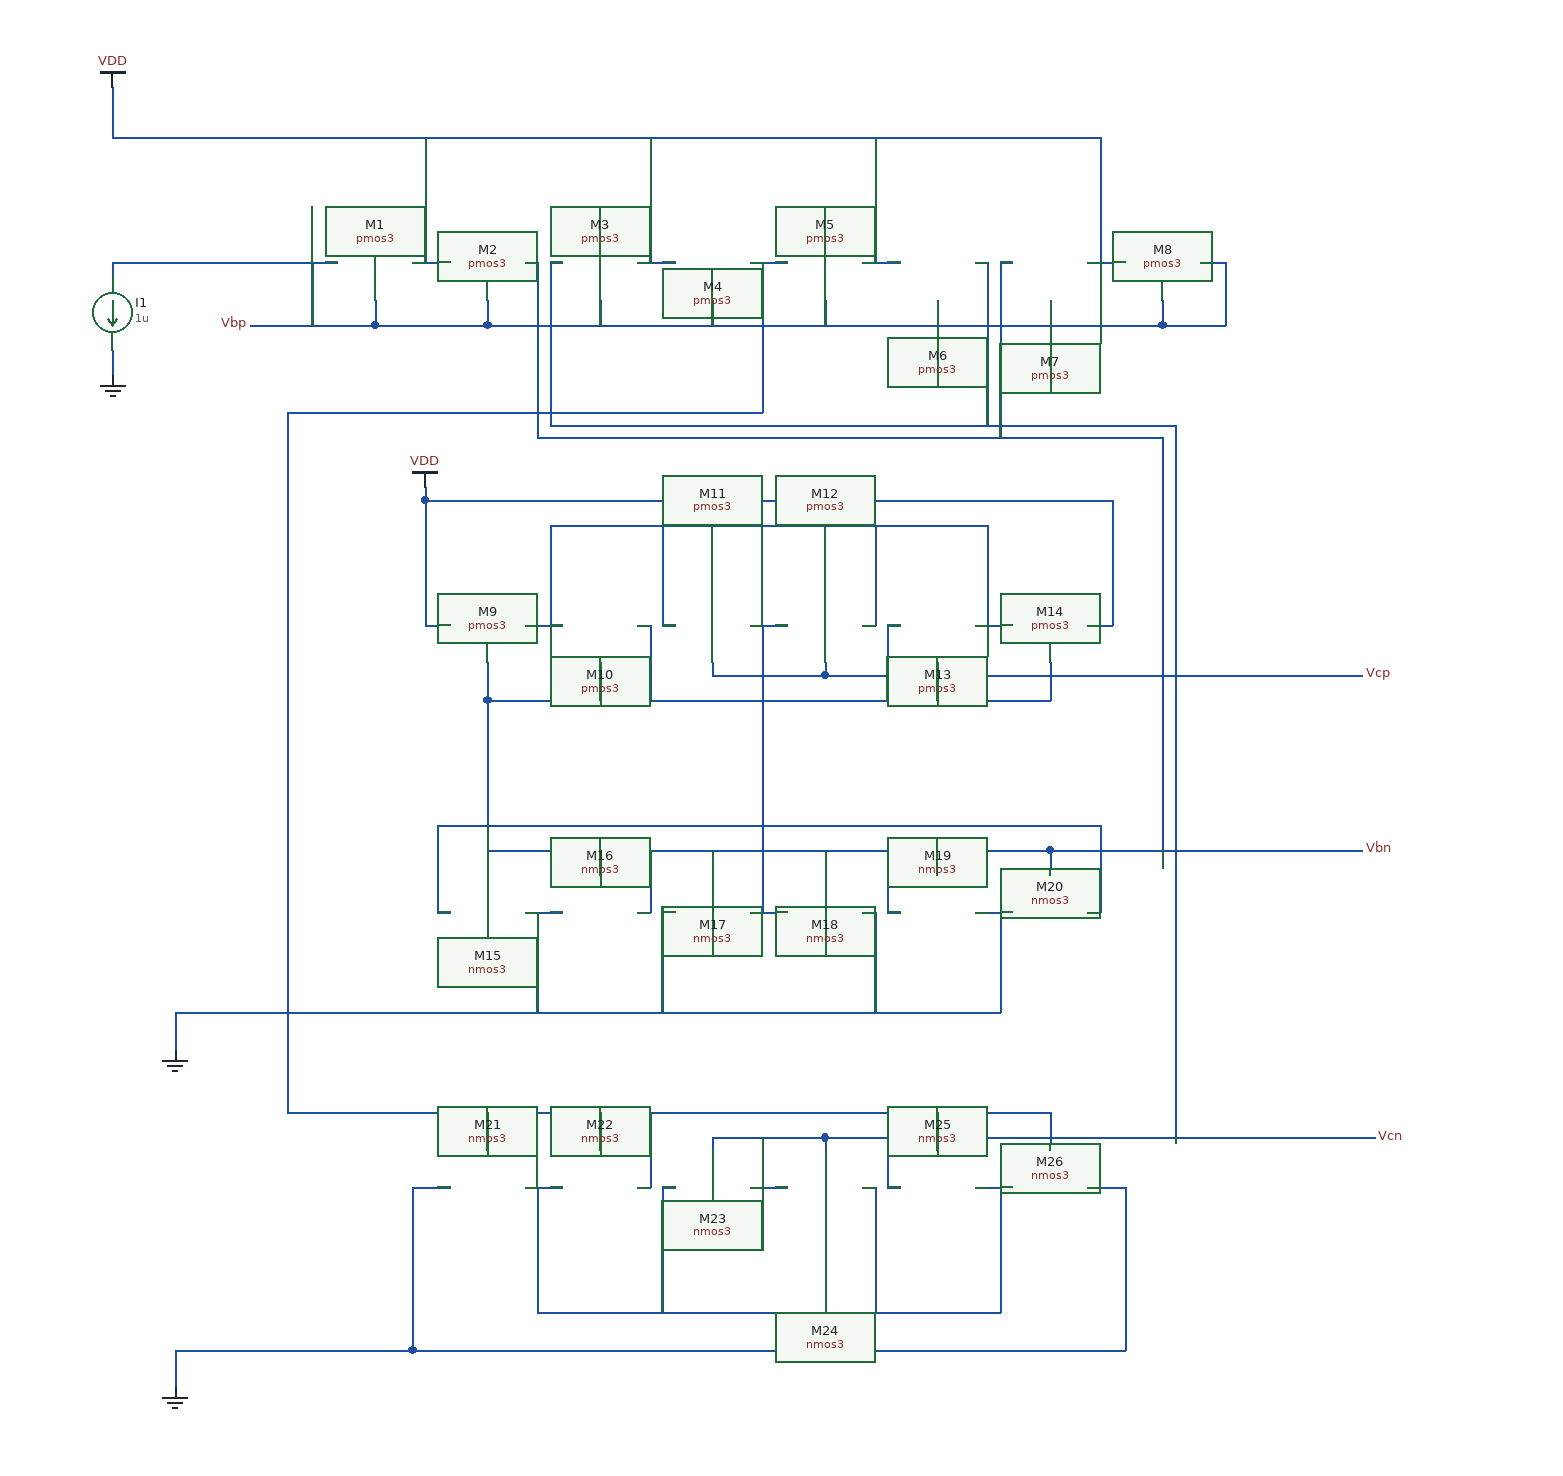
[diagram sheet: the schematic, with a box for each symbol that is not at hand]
v {xschem version=2.9.9 file_version=1.2 }
G {}
K {}
V {}
S {}
E {}
N 430 -980 430 -960 { lab=Vbp}
N 430 -960 520 -960 { lab=Vbp}
N 520 -980 520 -960 { lab=Vbp}
N 520 -960 1060 -960 { lab=Vbp}
N 1060 -980 1060 -960 { lab=Vbp}
N 970 -980 970 -960 { lab=Vbp}
N 880 -980 880 -960 { lab=Vbp}
N 790 -980 790 -960 { lab=Vbp}
N 700 -980 700 -960 { lab=Vbp}
N 610 -980 610 -960 { lab=Vbp}
N 330 -960 430 -960 { lab=Vbp}
N 220 -1010 400 -1010 { lab=Vbp}
N 220 -1010 220 -1000 { lab=Vbp}
N 220 -940 220 -920 { lab=GND}
N 460 -1010 490 -1010 { lab=VDD}
N 640 -1010 670 -1010 { lab=VDD}
N 820 -1010 850 -1010 { lab=VDD}
N 830 -1110 830 -1010 { lab=VDD}
N 220 -1110 920 -1110 { lab=VDD}
N 220 -1150 220 -1110 { lab=VDD}
N 470 -1110 470 -1010 { lab=VDD}
N 650 -1110 650 -1010 { lab=VDD}
N 380 -1010 380 -960 { lab=Vbp}
N 1090 -1010 1110 -1010 { lab=Vbp}
N 1110 -1010 1110 -960 { lab=Vbp}
N 1060 -960 1110 -960 { lab=Vbp}
N 470 -720 490 -720 { lab=VDD}
N 470 -800 470 -720 { lab=VDD}
N 1000 -720 1020 -720 { lab=VDD}
N 1020 -800 1020 -720 { lab=VDD}
N 470 -820 1020 -820 { lab=VDD}
N 520 -690 520 -670 { lab=#net1}
N 520 -660 970 -660 { lab=#net1}
N 970 -690 970 -670 { lab=#net1}
N 610 -690 610 -670 { lab=#net1}
N 880 -690 880 -670 { lab=#net1}
N 550 -720 580 -720 { lab=#net2}
N 910 -720 940 -720 { lab=#net2}
N 650 -720 650 -670 { lab=#net1}
N 640 -720 650 -720 { lab=#net1}
N 840 -720 850 -720 { lab=#net1}
N 840 -720 840 -670 { lab=#net1}
N 570 -800 570 -720 { lab=#net2}
N 570 -800 670 -800 { lab=#net2}
N 660 -800 660 -720 { lab=#net2}
N 920 -800 920 -720 { lab=#net2}
N 670 -800 920 -800 { lab=#net2}
N 830 -800 830 -720 { lab=#net2}
N 700 -690 700 -680 { lab=Vcp}
N 700 -680 790 -680 { lab=Vcp}
N 790 -690 790 -680 { lab=Vcp}
N 730 -720 760 -720 { lab=Vcp}
N 740 -720 740 -680 { lab=Vcp}
N 790 -680 1220 -680 { lab=Vcp}
N 520 -670 520 -660 { lab=#net1}
N 610 -670 610 -660 { lab=#net1}
N 650 -670 650 -660 { lab=#net1}
N 840 -670 840 -660 { lab=#net1}
N 880 -670 880 -660 { lab=#net1}
N 970 -670 970 -660 { lab=#net1}
N 660 -720 670 -720 { lab=#net2}
N 820 -720 830 -720 { lab=#net2}
N 470 -820 470 -800 { lab=VDD}
N 1020 -820 1020 -800 { lab=VDD}
N 470 -830 470 -820 { lab=VDD}
N 520 -660 520 -560 { lab=#net1}
N 520 -540 520 -520 { lab=Vbn}
N 520 -540 880 -540 { lab=Vbn}
N 880 -540 970 -540 { lab=Vbn}
N 970 -540 1220 -540 { lab=Vbn}
N 610 -540 610 -520 { lab=Vbn}
N 700 -540 700 -520 { lab=Vbn}
N 790 -540 790 -520 { lab=Vbn}
N 880 -540 880 -520 { lab=Vbn}
N 970 -540 970 -520 { lab=Vbn}
N 550 -490 580 -490 { lab=GND}
N 730 -490 760 -490 { lab=Vcp}
N 910 -490 940 -490 { lab=GND}
N 270 -410 440 -410 { lab=GND}
N 270 -410 270 -380 { lab=GND}
N 640 -490 650 -490 { lab=Vbn}
N 650 -540 650 -490 { lab=Vbn}
N 840 -490 850 -490 { lab=Vbn}
N 840 -540 840 -490 { lab=Vbn}
N 660 -490 670 -490 { lab=GND}
N 820 -490 830 -490 { lab=GND}
N 480 -490 490 -490 { lab=#net1}
N 480 -550 480 -490 { lab=#net1}
N 480 -560 480 -550 { lab=#net1}
N 480 -560 1010 -560 { lab=#net1}
N 1010 -550 1010 -490 { lab=#net1}
N 1000 -490 1010 -490 { lab=#net1}
N 1010 -560 1010 -550 { lab=#net1}
N 740 -680 740 -490 { lab=Vcp}
N 560 -490 560 -410 { lab=GND}
N 660 -490 660 -410 { lab=GND}
N 830 -490 830 -410 { lab=GND}
N 930 -490 930 -410 { lab=GND}
N 440 -410 930 -410 { lab=GND}
N 550 -1010 560 -1010 { lab=Vbn}
N 560 -1010 560 -870 { lab=Vbn}
N 560 -870 1060 -870 { lab=Vbn}
N 1060 -870 1060 -540 { lab=Vbn}
N 930 -1010 940 -1010 { lab=Vbn}
N 930 -1010 930 -870 { lab=Vbn}
N 570 -1010 580 -1010 { lab=Vbp}
N 570 -1010 570 -880 { lab=Vbp}
N 910 -1010 920 -1010 { lab=Vbp}
N 920 -1010 920 -880 { lab=Vbp}
N 570 -880 1010 -880 { lab=Vbp}
N 1010 -880 1070 -880 { lab=Vbp}
N 920 -1110 1010 -1110 { lab=VDD}
N 1010 -1110 1010 -1010 { lab=VDD}
N 1000 -1010 1030 -1010 { lab=VDD}
N 730 -1010 760 -1010 { lab=#net3}
N 740 -1010 740 -890 { lab=#net3}
N 360 -890 740 -890 { lab=#net3}
N 730 -270 760 -270 { lab=Vbp}
N 700 -310 700 -300 { lab=Vbp}
N 700 -310 790 -310 { lab=Vbp}
N 790 -310 790 -300 { lab=Vbp}
N 740 -310 740 -270 { lab=Vbp}
N 790 -310 1230 -310 { lab=Vbp}
N 460 -270 490 -270 { lab=GND}
N 460 -270 460 -190 { lab=GND}
N 460 -140 1030 -140 { lab=GND}
N 1030 -270 1030 -190 { lab=GND}
N 1000 -270 1030 -270 { lab=GND}
N 270 -140 460 -140 { lab=GND}
N 270 -140 270 -110 { lab=GND}
N 360 -350 360 -330 { lab=#net3}
N 360 -330 970 -330 { lab=#net3}
N 520 -330 520 -300 { lab=#net3}
N 610 -330 610 -300 { lab=#net3}
N 880 -330 880 -300 { lab=#net3}
N 970 -330 970 -300 { lab=#net3}
N 550 -270 580 -270 { lab=#net4}
N 910 -270 940 -270 { lab=#net4}
N 460 -180 460 -140 { lab=GND}
N 460 -190 460 -180 { lab=GND}
N 1030 -190 1030 -140 { lab=GND}
N 560 -270 560 -170 { lab=#net4}
N 560 -170 930 -170 { lab=#net4}
N 930 -270 930 -170 { lab=#net4}
N 660 -270 670 -270 { lab=#net4}
N 660 -270 660 -170 { lab=#net4}
N 820 -270 830 -270 { lab=#net4}
N 830 -270 830 -170 { lab=#net4}
N 640 -270 650 -270 { lab=#net3}
N 650 -330 650 -270 { lab=#net3}
N 840 -270 850 -270 { lab=#net3}
N 840 -330 840 -270 { lab=#net3}
N 1070 -330 1070 -310 { lab=Vbp}
N 1070 -880 1070 -330 { lab=Vbp}
N 360 -890 360 -350 { lab=#net3}
C {madvlsi/pmos3.sym} 430 -1010 3 0 {name=M1
L=0.5
W=12
body=VDD
nf=1
mult=1
ad="'int((nf+1)/2) * W/nf * 0.29'" 
pd="'2*int((nf+1)/2) * (W/nf + 0.29)'"
as="'int((nf+2)/2) * W/nf * 0.29'" 
ps="'2*int((nf+2)/2) * (W/nf + 0.29)'"
nrd="'0.29 / W'" nrs="'0.29 / W'"
sa=0 sb=0 sd=0
model=pfet_01v8
spiceprefix=X
}
C {madvlsi/pmos3.sym} 520 -1010 3 0 {name=M2
L=0.5
W=12
body=VDD
nf=1
mult=1
ad="'int((nf+1)/2) * W/nf * 0.29'" 
pd="'2*int((nf+1)/2) * (W/nf + 0.29)'"
as="'int((nf+2)/2) * W/nf * 0.29'" 
ps="'2*int((nf+2)/2) * (W/nf + 0.29)'"
nrd="'0.29 / W'" nrs="'0.29 / W'"
sa=0 sb=0 sd=0
model=pfet_01v8
spiceprefix=X
}
C {madvlsi/pmos3.sym} 610 -1010 3 0 {name=M3
L=0.5
W=12
body=VDD
nf=1
mult=1
ad="'int((nf+1)/2) * W/nf * 0.29'" 
pd="'2*int((nf+1)/2) * (W/nf + 0.29)'"
as="'int((nf+2)/2) * W/nf * 0.29'" 
ps="'2*int((nf+2)/2) * (W/nf + 0.29)'"
nrd="'0.29 / W'" nrs="'0.29 / W'"
sa=0 sb=0 sd=0
model=pfet_01v8
spiceprefix=X
}
C {madvlsi/pmos3.sym} 700 -1010 3 0 {name=M4
L=0.5
W=12
body=VDD
nf=1
mult=1
ad="'int((nf+1)/2) * W/nf * 0.29'" 
pd="'2*int((nf+1)/2) * (W/nf + 0.29)'"
as="'int((nf+2)/2) * W/nf * 0.29'" 
ps="'2*int((nf+2)/2) * (W/nf + 0.29)'"
nrd="'0.29 / W'" nrs="'0.29 / W'"
sa=0 sb=0 sd=0
model=pfet_01v8
spiceprefix=X
}
C {madvlsi/pmos3.sym} 790 -1010 3 0 {name=M5
L=0.5
W=12
body=VDD
nf=1
mult=1
ad="'int((nf+1)/2) * W/nf * 0.29'" 
pd="'2*int((nf+1)/2) * (W/nf + 0.29)'"
as="'int((nf+2)/2) * W/nf * 0.29'" 
ps="'2*int((nf+2)/2) * (W/nf + 0.29)'"
nrd="'0.29 / W'" nrs="'0.29 / W'"
sa=0 sb=0 sd=0
model=pfet_01v8
spiceprefix=X
}
C {madvlsi/pmos3.sym} 880 -1010 3 0 {name=M6
L=0.5
W=12
body=VDD
nf=1
mult=1
ad="'int((nf+1)/2) * W/nf * 0.29'" 
pd="'2*int((nf+1)/2) * (W/nf + 0.29)'"
as="'int((nf+2)/2) * W/nf * 0.29'" 
ps="'2*int((nf+2)/2) * (W/nf + 0.29)'"
nrd="'0.29 / W'" nrs="'0.29 / W'"
sa=0 sb=0 sd=0
model=pfet_01v8
spiceprefix=X
}
C {madvlsi/pmos3.sym} 970 -1010 3 0 {name=M7
L=0.5
W=12
body=VDD
nf=1
mult=1
ad="'int((nf+1)/2) * W/nf * 0.29'" 
pd="'2*int((nf+1)/2) * (W/nf + 0.29)'"
as="'int((nf+2)/2) * W/nf * 0.29'" 
ps="'2*int((nf+2)/2) * (W/nf + 0.29)'"
nrd="'0.29 / W'" nrs="'0.29 / W'"
sa=0 sb=0 sd=0
model=pfet_01v8
spiceprefix=X
}
C {madvlsi/pmos3.sym} 1060 -1010 3 0 {name=M8
L=0.5
W=12
body=VDD
nf=1
mult=1
ad="'int((nf+1)/2) * W/nf * 0.29'" 
pd="'2*int((nf+1)/2) * (W/nf + 0.29)'"
as="'int((nf+2)/2) * W/nf * 0.29'" 
ps="'2*int((nf+2)/2) * (W/nf + 0.29)'"
nrd="'0.29 / W'" nrs="'0.29 / W'"
sa=0 sb=0 sd=0
model=pfet_01v8
spiceprefix=X
}
C {madvlsi/pmos3.sym} 520 -720 3 0 {name=M9
L=0.5
W=12
body=VDD
nf=1
mult=1
ad="'int((nf+1)/2) * W/nf * 0.29'" 
pd="'2*int((nf+1)/2) * (W/nf + 0.29)'"
as="'int((nf+2)/2) * W/nf * 0.29'" 
ps="'2*int((nf+2)/2) * (W/nf + 0.29)'"
nrd="'0.29 / W'" nrs="'0.29 / W'"
sa=0 sb=0 sd=0
model=pfet_01v8
spiceprefix=X
}
C {madvlsi/pmos3.sym} 610 -720 3 0 {name=M10
L=0.5
W=12
body=VDD
nf=1
mult=1
ad="'int((nf+1)/2) * W/nf * 0.29'" 
pd="'2*int((nf+1)/2) * (W/nf + 0.29)'"
as="'int((nf+2)/2) * W/nf * 0.29'" 
ps="'2*int((nf+2)/2) * (W/nf + 0.29)'"
nrd="'0.29 / W'" nrs="'0.29 / W'"
sa=0 sb=0 sd=0
model=pfet_01v8
spiceprefix=X
}
C {madvlsi/pmos3.sym} 700 -720 3 0 {name=M11
L=0.5
W=12
body=VDD
nf=1
mult=1
ad="'int((nf+1)/2) * W/nf * 0.29'" 
pd="'2*int((nf+1)/2) * (W/nf + 0.29)'"
as="'int((nf+2)/2) * W/nf * 0.29'" 
ps="'2*int((nf+2)/2) * (W/nf + 0.29)'"
nrd="'0.29 / W'" nrs="'0.29 / W'"
sa=0 sb=0 sd=0
model=pfet_01v8
spiceprefix=X
}
C {madvlsi/pmos3.sym} 790 -720 3 0 {name=M12
L=0.5
W=12
body=VDD
nf=1
mult=1
ad="'int((nf+1)/2) * W/nf * 0.29'" 
pd="'2*int((nf+1)/2) * (W/nf + 0.29)'"
as="'int((nf+2)/2) * W/nf * 0.29'" 
ps="'2*int((nf+2)/2) * (W/nf + 0.29)'"
nrd="'0.29 / W'" nrs="'0.29 / W'"
sa=0 sb=0 sd=0
model=pfet_01v8
spiceprefix=X
}
C {madvlsi/pmos3.sym} 880 -720 3 0 {name=M13
L=0.5
W=12
body=VDD
nf=1
mult=1
ad="'int((nf+1)/2) * W/nf * 0.29'" 
pd="'2*int((nf+1)/2) * (W/nf + 0.29)'"
as="'int((nf+2)/2) * W/nf * 0.29'" 
ps="'2*int((nf+2)/2) * (W/nf + 0.29)'"
nrd="'0.29 / W'" nrs="'0.29 / W'"
sa=0 sb=0 sd=0
model=pfet_01v8
spiceprefix=X
}
C {madvlsi/pmos3.sym} 970 -720 3 0 {name=M14
L=0.5
W=12
body=VDD
nf=1
mult=1
ad="'int((nf+1)/2) * W/nf * 0.29'" 
pd="'2*int((nf+1)/2) * (W/nf + 0.29)'"
as="'int((nf+2)/2) * W/nf * 0.29'" 
ps="'2*int((nf+2)/2) * (W/nf + 0.29)'"
nrd="'0.29 / W'" nrs="'0.29 / W'"
sa=0 sb=0 sd=0
model=pfet_01v8
spiceprefix=X
}
C {madvlsi/nmos3.sym} 520 -490 1 0 {name=M15
L=0.5
W=12
body=GND
nf=1
mult=1
ad="'int((nf+1)/2) * W/nf * 0.29'" 
pd="'2*int((nf+1)/2) * (W/nf + 0.29)'"
as="'int((nf+2)/2) * W/nf * 0.29'" 
ps="'2*int((nf+2)/2) * (W/nf + 0.29)'"
nrd="'0.29 / W'" nrs="'0.29 / W'"
sa=0 sb=0 sd=0
model=nfet_01v8
spiceprefix=X
}
C {madvlsi/nmos3.sym} 610 -490 1 0 {name=M16
L=0.5
W=12
body=GND
nf=1
mult=1
ad="'int((nf+1)/2) * W/nf * 0.29'" 
pd="'2*int((nf+1)/2) * (W/nf + 0.29)'"
as="'int((nf+2)/2) * W/nf * 0.29'" 
ps="'2*int((nf+2)/2) * (W/nf + 0.29)'"
nrd="'0.29 / W'" nrs="'0.29 / W'"
sa=0 sb=0 sd=0
model=nfet_01v8
spiceprefix=X
}
C {madvlsi/nmos3.sym} 700 -490 1 0 {name=M17
L=0.5
W=12
body=GND
nf=1
mult=1
ad="'int((nf+1)/2) * W/nf * 0.29'" 
pd="'2*int((nf+1)/2) * (W/nf + 0.29)'"
as="'int((nf+2)/2) * W/nf * 0.29'" 
ps="'2*int((nf+2)/2) * (W/nf + 0.29)'"
nrd="'0.29 / W'" nrs="'0.29 / W'"
sa=0 sb=0 sd=0
model=nfet_01v8
spiceprefix=X
}
C {madvlsi/nmos3.sym} 790 -490 1 0 {name=M18
L=0.5
W=12
body=GND
nf=1
mult=1
ad="'int((nf+1)/2) * W/nf * 0.29'" 
pd="'2*int((nf+1)/2) * (W/nf + 0.29)'"
as="'int((nf+2)/2) * W/nf * 0.29'" 
ps="'2*int((nf+2)/2) * (W/nf + 0.29)'"
nrd="'0.29 / W'" nrs="'0.29 / W'"
sa=0 sb=0 sd=0
model=nfet_01v8
spiceprefix=X
}
C {madvlsi/nmos3.sym} 880 -490 1 0 {name=M19
L=0.5
W=12
body=GND
nf=1
mult=1
ad="'int((nf+1)/2) * W/nf * 0.29'" 
pd="'2*int((nf+1)/2) * (W/nf + 0.29)'"
as="'int((nf+2)/2) * W/nf * 0.29'" 
ps="'2*int((nf+2)/2) * (W/nf + 0.29)'"
nrd="'0.29 / W'" nrs="'0.29 / W'"
sa=0 sb=0 sd=0
model=nfet_01v8
spiceprefix=X
}
C {madvlsi/nmos3.sym} 970 -490 1 0 {name=M20
L=0.5
W=12
body=GND
nf=1
mult=1
ad="'int((nf+1)/2) * W/nf * 0.29'" 
pd="'2*int((nf+1)/2) * (W/nf + 0.29)'"
as="'int((nf+2)/2) * W/nf * 0.29'" 
ps="'2*int((nf+2)/2) * (W/nf + 0.29)'"
nrd="'0.29 / W'" nrs="'0.29 / W'"
sa=0 sb=0 sd=0
model=nfet_01v8
spiceprefix=X
}
C {madvlsi/nmos3.sym} 520 -270 1 0 {name=M21
L=0.5
W=12
body=GND
nf=1
mult=1
ad="'int((nf+1)/2) * W/nf * 0.29'" 
pd="'2*int((nf+1)/2) * (W/nf + 0.29)'"
as="'int((nf+2)/2) * W/nf * 0.29'" 
ps="'2*int((nf+2)/2) * (W/nf + 0.29)'"
nrd="'0.29 / W'" nrs="'0.29 / W'"
sa=0 sb=0 sd=0
model=nfet_01v8
spiceprefix=X
}
C {madvlsi/nmos3.sym} 610 -270 1 0 {name=M22
L=0.5
W=12
body=GND
nf=1
mult=1
ad="'int((nf+1)/2) * W/nf * 0.29'" 
pd="'2*int((nf+1)/2) * (W/nf + 0.29)'"
as="'int((nf+2)/2) * W/nf * 0.29'" 
ps="'2*int((nf+2)/2) * (W/nf + 0.29)'"
nrd="'0.29 / W'" nrs="'0.29 / W'"
sa=0 sb=0 sd=0
model=nfet_01v8
spiceprefix=X
}
C {madvlsi/nmos3.sym} 700 -270 1 0 {name=M23
L=0.5
W=12
body=GND
nf=1
mult=1
ad="'int((nf+1)/2) * W/nf * 0.29'" 
pd="'2*int((nf+1)/2) * (W/nf + 0.29)'"
as="'int((nf+2)/2) * W/nf * 0.29'" 
ps="'2*int((nf+2)/2) * (W/nf + 0.29)'"
nrd="'0.29 / W'" nrs="'0.29 / W'"
sa=0 sb=0 sd=0
model=nfet_01v8
spiceprefix=X
}
C {madvlsi/nmos3.sym} 790 -270 1 0 {name=M24
L=0.5
W=12
body=GND
nf=1
mult=1
ad="'int((nf+1)/2) * W/nf * 0.29'" 
pd="'2*int((nf+1)/2) * (W/nf + 0.29)'"
as="'int((nf+2)/2) * W/nf * 0.29'" 
ps="'2*int((nf+2)/2) * (W/nf + 0.29)'"
nrd="'0.29 / W'" nrs="'0.29 / W'"
sa=0 sb=0 sd=0
model=nfet_01v8
spiceprefix=X
}
C {madvlsi/nmos3.sym} 880 -270 1 0 {name=M25
L=0.5
W=12
body=GND
nf=1
mult=1
ad="'int((nf+1)/2) * W/nf * 0.29'" 
pd="'2*int((nf+1)/2) * (W/nf + 0.29)'"
as="'int((nf+2)/2) * W/nf * 0.29'" 
ps="'2*int((nf+2)/2) * (W/nf + 0.29)'"
nrd="'0.29 / W'" nrs="'0.29 / W'"
sa=0 sb=0 sd=0
model=nfet_01v8
spiceprefix=X
}
C {madvlsi/nmos3.sym} 970 -270 1 0 {name=M26
L=0.5
W=12
body=GND
nf=1
mult=1
ad="'int((nf+1)/2) * W/nf * 0.29'" 
pd="'2*int((nf+1)/2) * (W/nf + 0.29)'"
as="'int((nf+2)/2) * W/nf * 0.29'" 
ps="'2*int((nf+2)/2) * (W/nf + 0.29)'"
nrd="'0.29 / W'" nrs="'0.29 / W'"
sa=0 sb=0 sd=0
model=nfet_01v8
spiceprefix=X
}
C {devices/lab_pin.sym} 330 -960 0 0 {name=l2 sig_type=std_logic lab=Vbp}
C {madvlsi/isource.sym} 220 -970 0 0 {name=I1
value=1u}
C {madvlsi/gnd.sym} 220 -920 0 0 {name=l1 lab=GND}
C {madvlsi/vdd.sym} 220 -1150 0 0 {name=l3 lab=VDD}
C {madvlsi/vdd.sym} 470 -830 0 0 {name=l4 lab=VDD}
C {madvlsi/gnd.sym} 270 -380 0 0 {name=l5 lab=GND}
C {madvlsi/gnd.sym} 270 -110 0 0 {name=l6 lab=GND}
C {devices/lab_pin.sym} 1220 -680 2 0 {name=l7 sig_type=std_logic lab=Vcp}
C {devices/lab_pin.sym} 1220 -540 2 0 {name=l8 sig_type=std_logic lab=Vbn}
C {devices/lab_pin.sym} 1230 -310 2 0 {name=l9 sig_type=std_logic lab=Vcn}
